VERSION 5.7 ;
  NOWIREEXTENSIONATPIN ON ;
  DIVIDERCHAR "/" ;
  BUSBITCHARS "[]" ;
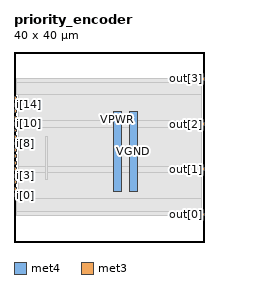
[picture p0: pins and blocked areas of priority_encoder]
MACRO priority_encoder
  CLASS BLOCK ;
  FOREIGN priority_encoder ;
  ORIGIN 0.000 0.000 ;
  SIZE 40.000 BY 40.000 ;
  PIN VGND
    DIRECTION INOUT ;
    USE GROUND ;
    PORT
      LAYER met4 ;
        RECT 24.340 10.640 25.940 27.440 ;
    END
  END VGND
  PIN VPWR
    DIRECTION INOUT ;
    USE POWER ;
    PORT
      LAYER met4 ;
        RECT 21.040 10.640 22.640 27.440 ;
    END
  END VPWR
  PIN i[0]
    DIRECTION INPUT ;
    USE SIGNAL ;
    PORT
      LAYER met3 ;
        RECT 0.000 9.560 0.600 10.160 ;
    END
  END i[0]
  PIN i[10]
    DIRECTION INPUT ;
    USE SIGNAL ;
    ANTENNAGATEAREA 0.159000 ;
    PORT
      LAYER met3 ;
        RECT 0.000 23.160 0.600 23.760 ;
    END
  END i[10]
  PIN i[11]
    DIRECTION INPUT ;
    USE SIGNAL ;
    ANTENNAGATEAREA 0.159000 ;
    PORT
      LAYER met3 ;
        RECT 0.000 24.520 0.600 25.120 ;
    END
  END i[11]
  PIN i[12]
    DIRECTION INPUT ;
    USE SIGNAL ;
    ANTENNAGATEAREA 0.159000 ;
    PORT
      LAYER met3 ;
        RECT 0.000 25.880 0.600 26.480 ;
    END
  END i[12]
  PIN i[13]
    DIRECTION INPUT ;
    USE SIGNAL ;
    ANTENNAGATEAREA 0.159000 ;
    PORT
      LAYER met3 ;
        RECT 0.000 27.240 0.600 27.840 ;
    END
  END i[13]
  PIN i[14]
    DIRECTION INPUT ;
    USE SIGNAL ;
    ANTENNAGATEAREA 0.159000 ;
    PORT
      LAYER met3 ;
        RECT 0.000 28.600 0.600 29.200 ;
    END
  END i[14]
  PIN i[15]
    DIRECTION INPUT ;
    USE SIGNAL ;
    ANTENNAGATEAREA 0.159000 ;
    PORT
      LAYER met3 ;
        RECT 0.000 29.960 0.600 30.560 ;
    END
  END i[15]
  PIN i[1]
    DIRECTION INPUT ;
    USE SIGNAL ;
    ANTENNAGATEAREA 0.159000 ;
    PORT
      LAYER met3 ;
        RECT 0.000 10.920 0.600 11.520 ;
    END
  END i[1]
  PIN i[2]
    DIRECTION INPUT ;
    USE SIGNAL ;
    ANTENNAGATEAREA 0.159000 ;
    PORT
      LAYER met3 ;
        RECT 0.000 12.280 0.600 12.880 ;
    END
  END i[2]
  PIN i[3]
    DIRECTION INPUT ;
    USE SIGNAL ;
    ANTENNAGATEAREA 0.159000 ;
    PORT
      LAYER met3 ;
        RECT 0.000 13.640 0.600 14.240 ;
    END
  END i[3]
  PIN i[4]
    DIRECTION INPUT ;
    USE SIGNAL ;
    ANTENNAGATEAREA 0.159000 ;
    PORT
      LAYER met3 ;
        RECT 0.000 15.000 0.600 15.600 ;
    END
  END i[4]
  PIN i[5]
    DIRECTION INPUT ;
    USE SIGNAL ;
    ANTENNAGATEAREA 0.159000 ;
    PORT
      LAYER met3 ;
        RECT 0.000 16.360 0.600 16.960 ;
    END
  END i[5]
  PIN i[6]
    DIRECTION INPUT ;
    USE SIGNAL ;
    ANTENNAGATEAREA 0.159000 ;
    PORT
      LAYER met3 ;
        RECT 0.000 17.720 0.600 18.320 ;
    END
  END i[6]
  PIN i[7]
    DIRECTION INPUT ;
    USE SIGNAL ;
    ANTENNAGATEAREA 0.159000 ;
    PORT
      LAYER met3 ;
        RECT 0.000 19.080 0.600 19.680 ;
    END
  END i[7]
  PIN i[8]
    DIRECTION INPUT ;
    USE SIGNAL ;
    ANTENNAGATEAREA 0.159000 ;
    PORT
      LAYER met3 ;
        RECT 0.000 20.440 0.600 21.040 ;
    END
  END i[8]
  PIN i[9]
    DIRECTION INPUT ;
    USE SIGNAL ;
    ANTENNAGATEAREA 0.159000 ;
    PORT
      LAYER met3 ;
        RECT 0.000 21.800 0.600 22.400 ;
    END
  END i[9]
  PIN out[0]
    DIRECTION OUTPUT ;
    USE SIGNAL ;
    ANTENNADIFFAREA 0.445500 ;
    PORT
      LAYER met3 ;
        RECT 39.400 5.480 40.000 6.080 ;
    END
  END out[0]
  PIN out[1]
    DIRECTION OUTPUT ;
    USE SIGNAL ;
    ANTENNADIFFAREA 0.445500 ;
    PORT
      LAYER met3 ;
        RECT 39.400 15.000 40.000 15.600 ;
    END
  END out[1]
  PIN out[2]
    DIRECTION OUTPUT ;
    USE SIGNAL ;
    ANTENNADIFFAREA 0.445500 ;
    PORT
      LAYER met3 ;
        RECT 39.400 24.520 40.000 25.120 ;
    END
  END out[2]
  PIN out[3]
    DIRECTION OUTPUT ;
    USE SIGNAL ;
    ANTENNADIFFAREA 0.445500 ;
    PORT
      LAYER met3 ;
        RECT 39.400 34.040 40.000 34.640 ;
    END
  END out[3]
  OBS
      LAYER nwell ;
        RECT 5.330 10.795 34.230 27.285 ;
      LAYER li1 ;
        RECT 5.520 10.795 34.040 27.285 ;
      LAYER met1 ;
        RECT 0.990 10.640 34.040 27.440 ;
      LAYER met2 ;
        RECT 1.010 5.595 32.110 34.525 ;
      LAYER met3 ;
        RECT 0.600 33.640 39.000 34.505 ;
        RECT 0.600 30.960 39.400 33.640 ;
        RECT 1.000 25.520 39.400 30.960 ;
        RECT 1.000 24.120 39.000 25.520 ;
        RECT 1.000 16.000 39.400 24.120 ;
        RECT 1.000 14.600 39.000 16.000 ;
        RECT 1.000 9.160 39.400 14.600 ;
        RECT 0.600 6.480 39.400 9.160 ;
        RECT 0.600 5.615 39.000 6.480 ;
      LAYER met4 ;
        RECT 6.735 13.095 7.065 22.265 ;
  END
END priority_encoder
END LIBRARY

